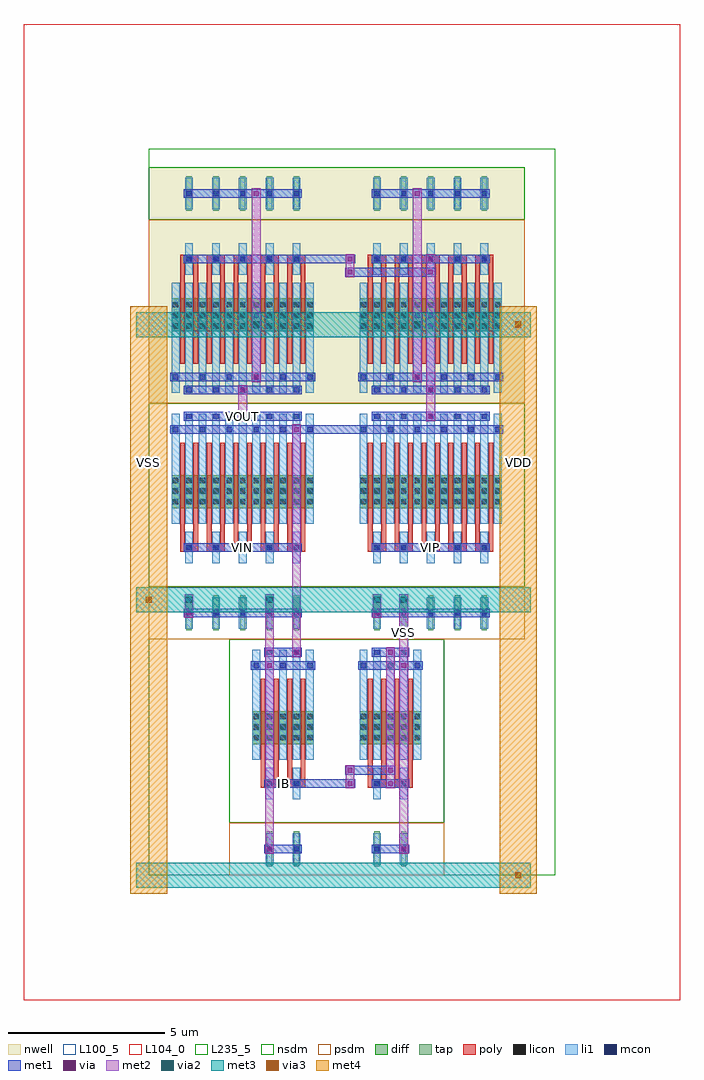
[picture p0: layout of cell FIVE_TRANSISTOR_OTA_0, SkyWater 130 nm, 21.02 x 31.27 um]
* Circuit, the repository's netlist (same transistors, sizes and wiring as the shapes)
* NGSPICE file created from FIVE_TRANSISTOR_OTA_0.ext - technology: sky130A

.subckt NMOS_4T_70086367_X5_Y1_1772456397 a_230_462# a_200_252# a_147_462# a_241_1232#
X0 a_230_462# a_200_252# a_147_462# a_241_1232# sky130_fd_pr__nfet_01v8 ad=0.147 pd=1.33 as=0.147 ps=1.33 w=1.05 l=0.15 M=10
.ends

.subckt NMOS_S_12526843_X2_Y1_1772456398 a_230_462# a_200_252# a_147_462#
X0 a_230_462# a_200_252# a_147_462# a_147_462# sky130_fd_pr__nfet_01v8 ad=0.147 pd=1.33 as=0.147 ps=1.33 w=1.05 l=0.15 M=4
.ends

.subckt DCL_NMOS_S_92974257_X2_Y1_1772456395 a_200_252# a_147_462#
X0 a_200_252# a_200_252# a_147_462# a_147_462# sky130_fd_pr__nfet_01v8 ad=0.147 pd=1.33 as=0.147 ps=1.33 w=1.05 l=0.15 M=4
.ends

.subckt PMOS_S_72546662_X5_Y1_1772456399 a_230_462# a_200_252# w_0_0#
X0 a_230_462# a_200_252# w_0_0# w_0_0# sky130_fd_pr__pfet_01v8 ad=0.147 pd=1.33 as=0.147 ps=1.33 w=1.05 l=0.15 M=10
.ends

.subckt DCL_PMOS_S_56423641_X5_Y1_1772456396 a_200_252# w_0_0#
X0 a_200_252# a_200_252# w_0_0# w_0_0# sky130_fd_pr__pfet_01v8 ad=0.147 pd=1.33 as=0.147 ps=1.33 w=1.05 l=0.15 M=10
.ends

.subckt FIVE_TRANSISTOR_OTA_0 IB VOUT VIP VIN VSS VDD
XNMOS_4T_70086367_X5_Y1_1772456397_0 VOUT VIN m1_914_1400# VSS NMOS_4T_70086367_X5_Y1_1772456397
XNMOS_4T_70086367_X5_Y1_1772456397_1 m1_946_3920# VIP m1_914_1400# VSS NMOS_4T_70086367_X5_Y1_1772456397
XNMOS_S_12526843_X2_Y1_1772456398_0 m1_914_1400# IB VSS NMOS_S_12526843_X2_Y1_1772456398
XDCL_NMOS_S_92974257_X2_Y1_1772456395_0 IB VSS DCL_NMOS_S_92974257_X2_Y1_1772456395
XPMOS_S_72546662_X5_Y1_1772456399_0 VOUT m1_946_3920# VDD PMOS_S_72546662_X5_Y1_1772456399
XDCL_PMOS_S_56423641_X5_Y1_1772456396_0 m1_946_3920# VDD DCL_PMOS_S_56423641_X5_Y1_1772456396
.ends

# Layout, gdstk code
from math import pi, radians
import gdstk
lib = gdstk.Library(unit=1e-6, precision=1e-09)
def R(c, l, rs):  # rectangles x0, y0, x1, y1
    for r in rs: c.add(gdstk.rectangle(r[:2], r[2:], *l))
def A(c, l, x, y, w, h, nx, ny, dx, dy):  # array of equal rectangles
    R(c, l, [(x+i*dx, y+j*dy, x+i*dx+w, y+j*dy+h) for i in range(nx) for j in range(ny)])
def P(c, l, *ps):  # polygons
    for p in ps: c.add(gdstk.Polygon(p, *l))
nwell = (64, 20)
diff = (65, 20)
tap = (65, 44)
poly = (66, 20)
licon = (66, 44)
li1 = (67, 20)
mcon = (67, 44)
met1 = (68, 20)
via = (68, 44)
met2 = (69, 20)
via2 = (69, 44)
met3 = (70, 20)
via3 = (70, 44)
met4 = (71, 20)
nsdm = (93, 44)
psdm = (94, 20)
L100_5 = (100, 5)
L104_0 = (104, 0)
L235_5 = (235, 5)

dcl_nmos_s_92974257_x2_y = lib.new_cell('DCL_NMOS_S_92974257_X2_Y1_1772456395')
R(dcl_nmos_s_92974257_x2_y, diff, [(0.735,2.31,2.705,3.36)])
R(dcl_nmos_s_92974257_x2_y, tap, [(1.205,6.16,1.375,7.28), (2.065,6.16,2.235,7.28)])
A(dcl_nmos_s_92974257_x2_y, poly, 1, 1.26, 0.15, 3.36, 4, 1, 0.43, 0)
R(dcl_nmos_s_92974257_x2_y, poly, [(1,4.485,1.58,4.755), (1.86,4.485,2.44,4.755)])
A(dcl_nmos_s_92974257_x2_y, licon, 0.775, 2.39, 0.17, 0.17, 3, 3, 0.43, 0.34)
A(dcl_nmos_s_92974257_x2_y, licon, 1.635, 2.39, 0.17, 0.17, 3, 3, 0.43, 0.34)
R(dcl_nmos_s_92974257_x2_y, licon, [(1.205,4.535,1.375,4.705), (2.065,4.535,2.235,4.705), (1.205,6.635,1.375,6.805), (2.065,6.635,2.235,6.805)])
A(dcl_nmos_s_92974257_x2_y, li1, 0.735, 0.335, 0.25, 3.53, 5, 1, 0.43, 0)
R(dcl_nmos_s_92974257_x2_y, li1, [(1.165,4.115,1.415,5.125), (2.025,4.115,2.275,5.125), (1.165,6.215,1.415,7.225), (2.025,6.215,2.275,7.225)])
A(dcl_nmos_s_92974257_x2_y, mcon, 0.775, 0.755, 0.17, 0.17, 3, 1, 0.86, 0)
R(dcl_nmos_s_92974257_x2_y, mcon, [(1.205,0.335,1.375,0.505), (2.065,0.335,2.235,0.505), (1.205,4.535,1.375,4.705), (2.065,4.535,2.235,4.705), (1.205,6.635,1.375,6.805), (2.065,6.635,2.235,6.805)])
R(dcl_nmos_s_92974257_x2_y, met1, [(1.12,0.28,2.32,0.56), (0.69,0.7,2.75,0.98), (1.12,4.48,2.32,4.76), (1.12,6.58,2.32,6.86)])
R(dcl_nmos_s_92974257_x2_y, via, [(1.645,0.345,1.795,0.495), (2.075,0.765,2.225,0.915), (1.645,4.545,1.795,4.695), (2.075,6.645,2.225,6.795)])
R(dcl_nmos_s_92974257_x2_y, met2, [(1.58,0.26,1.86,4.78), (2.01,0.68,2.29,6.88)])
R(dcl_nmos_s_92974257_x2_y, nsdm, [(0,0,3.44,5.88)])
R(dcl_nmos_s_92974257_x2_y, psdm, [(0,5.88,3.44,7.56)])
R(dcl_nmos_s_92974257_x2_y, L100_5, [(0,0,3.44,7.56)])

dcl_pmos_s_56423641_x5_y = lib.new_cell('DCL_PMOS_S_56423641_X5_Y1_1772456396')
R(dcl_pmos_s_56423641_x5_y, nwell, [(0,0,6.02,7.56)])
R(dcl_pmos_s_56423641_x5_y, diff, [(0.735,2.31,5.285,3.36)])
A(dcl_pmos_s_56423641_x5_y, tap, 1.205, 6.16, 0.17, 1.12, 5, 1, 0.86, 0)
A(dcl_pmos_s_56423641_x5_y, poly, 1, 1.26, 0.15, 3.36, 10, 1, 0.43, 0)
A(dcl_pmos_s_56423641_x5_y, poly, 1, 4.485, 0.58, 0.27, 5, 1, 0.86, 0)
A(dcl_pmos_s_56423641_x5_y, licon, 0.775, 2.39, 0.17, 0.17, 3, 3, 0.43, 0.34)
A(dcl_pmos_s_56423641_x5_y, licon, 1.635, 2.39, 0.17, 0.17, 3, 3, 0.43, 0.34)
A(dcl_pmos_s_56423641_x5_y, licon, 2.495, 2.39, 0.17, 0.17, 3, 3, 0.43, 0.34)
A(dcl_pmos_s_56423641_x5_y, licon, 3.355, 2.39, 0.17, 0.17, 3, 3, 0.43, 0.34)
A(dcl_pmos_s_56423641_x5_y, licon, 4.215, 2.39, 0.17, 0.17, 3, 3, 0.43, 0.34)
A(dcl_pmos_s_56423641_x5_y, licon, 1.205, 4.535, 0.17, 0.17, 5, 2, 0.86, 2.1)
A(dcl_pmos_s_56423641_x5_y, li1, 0.735, 0.335, 0.25, 3.53, 11, 1, 0.43, 0)
A(dcl_pmos_s_56423641_x5_y, li1, 1.165, 4.115, 0.25, 1.01, 5, 2, 0.86, 2.1)
A(dcl_pmos_s_56423641_x5_y, mcon, 1.205, 0.335, 0.17, 0.17, 5, 2, 0.86, 4.2)
A(dcl_pmos_s_56423641_x5_y, mcon, 0.775, 0.755, 0.17, 0.17, 6, 1, 0.86, 0)
A(dcl_pmos_s_56423641_x5_y, mcon, 1.205, 6.635, 0.17, 0.17, 5, 1, 0.86, 0)
R(dcl_pmos_s_56423641_x5_y, met1, [(1.12,0.28,4.9,0.56), (0.69,0.7,5.33,0.98), (1.12,4.48,4.9,4.76), (1.12,6.58,4.9,6.86)])
R(dcl_pmos_s_56423641_x5_y, via, [(2.935,0.345,3.085,0.495), (3.365,0.765,3.515,0.915), (2.935,4.545,3.085,4.695), (3.365,6.645,3.515,6.795)])
R(dcl_pmos_s_56423641_x5_y, met2, [(2.87,0.26,3.15,4.78), (3.3,0.68,3.58,6.88)])
R(dcl_pmos_s_56423641_x5_y, nsdm, [(0,5.88,6.02,7.56)])
R(dcl_pmos_s_56423641_x5_y, psdm, [(0,0,6.02,5.88)])
R(dcl_pmos_s_56423641_x5_y, L100_5, [(0,0,6.02,7.56)])

nmos_s_12526843_x2_y1_17 = lib.new_cell('NMOS_S_12526843_X2_Y1_1772456398')
R(nmos_s_12526843_x2_y1_17, diff, [(0.735,2.31,2.705,3.36)])
R(nmos_s_12526843_x2_y1_17, tap, [(1.205,6.16,1.375,7.28), (2.065,6.16,2.235,7.28)])
A(nmos_s_12526843_x2_y1_17, poly, 1, 1.26, 0.15, 3.36, 4, 1, 0.43, 0)
R(nmos_s_12526843_x2_y1_17, poly, [(1,4.485,1.58,4.755), (1.86,4.485,2.44,4.755)])
A(nmos_s_12526843_x2_y1_17, licon, 0.775, 2.39, 0.17, 0.17, 3, 3, 0.43, 0.34)
A(nmos_s_12526843_x2_y1_17, licon, 1.635, 2.39, 0.17, 0.17, 3, 3, 0.43, 0.34)
R(nmos_s_12526843_x2_y1_17, licon, [(1.205,4.535,1.375,4.705), (2.065,4.535,2.235,4.705), (1.205,6.635,1.375,6.805), (2.065,6.635,2.235,6.805)])
A(nmos_s_12526843_x2_y1_17, li1, 0.735, 0.335, 0.25, 3.53, 5, 1, 0.43, 0)
R(nmos_s_12526843_x2_y1_17, li1, [(1.165,4.115,1.415,5.125), (2.025,4.115,2.275,5.125), (1.165,6.215,1.415,7.225), (2.025,6.215,2.275,7.225)])
A(nmos_s_12526843_x2_y1_17, mcon, 0.775, 0.755, 0.17, 0.17, 3, 1, 0.86, 0)
R(nmos_s_12526843_x2_y1_17, mcon, [(1.205,0.335,1.375,0.505), (2.065,0.335,2.235,0.505), (1.205,4.535,1.375,4.705), (2.065,4.535,2.235,4.705), (1.205,6.635,1.375,6.805), (2.065,6.635,2.235,6.805)])
R(nmos_s_12526843_x2_y1_17, met1, [(1.12,0.28,2.32,0.56), (0.69,0.7,2.75,0.98), (1.12,4.48,2.32,4.76), (1.12,6.58,2.32,6.86)])
R(nmos_s_12526843_x2_y1_17, via, [(2.075,0.765,2.225,0.915), (2.075,6.645,2.225,6.795)])
R(nmos_s_12526843_x2_y1_17, met2, [(2.01,0.68,2.29,6.88)])
R(nmos_s_12526843_x2_y1_17, nsdm, [(0,0,3.44,5.88)])
R(nmos_s_12526843_x2_y1_17, psdm, [(0,5.88,3.44,7.56)])
R(nmos_s_12526843_x2_y1_17, L100_5, [(0,0,3.44,7.56)])

pmos_s_72546662_x5_y1_17 = lib.new_cell('PMOS_S_72546662_X5_Y1_1772456399')
R(pmos_s_72546662_x5_y1_17, nwell, [(0,0,6.02,7.56)])
R(pmos_s_72546662_x5_y1_17, diff, [(0.735,2.31,5.285,3.36)])
A(pmos_s_72546662_x5_y1_17, tap, 1.205, 6.16, 0.17, 1.12, 5, 1, 0.86, 0)
A(pmos_s_72546662_x5_y1_17, poly, 1, 1.26, 0.15, 3.36, 10, 1, 0.43, 0)
A(pmos_s_72546662_x5_y1_17, poly, 1, 4.485, 0.58, 0.27, 5, 1, 0.86, 0)
A(pmos_s_72546662_x5_y1_17, licon, 0.775, 2.39, 0.17, 0.17, 3, 3, 0.43, 0.34)
A(pmos_s_72546662_x5_y1_17, licon, 1.635, 2.39, 0.17, 0.17, 3, 3, 0.43, 0.34)
A(pmos_s_72546662_x5_y1_17, licon, 2.495, 2.39, 0.17, 0.17, 3, 3, 0.43, 0.34)
A(pmos_s_72546662_x5_y1_17, licon, 3.355, 2.39, 0.17, 0.17, 3, 3, 0.43, 0.34)
A(pmos_s_72546662_x5_y1_17, licon, 4.215, 2.39, 0.17, 0.17, 3, 3, 0.43, 0.34)
A(pmos_s_72546662_x5_y1_17, licon, 1.205, 4.535, 0.17, 0.17, 5, 2, 0.86, 2.1)
A(pmos_s_72546662_x5_y1_17, li1, 0.735, 0.335, 0.25, 3.53, 11, 1, 0.43, 0)
A(pmos_s_72546662_x5_y1_17, li1, 1.165, 4.115, 0.25, 1.01, 5, 2, 0.86, 2.1)
A(pmos_s_72546662_x5_y1_17, mcon, 1.205, 0.335, 0.17, 0.17, 5, 2, 0.86, 4.2)
A(pmos_s_72546662_x5_y1_17, mcon, 0.775, 0.755, 0.17, 0.17, 6, 1, 0.86, 0)
A(pmos_s_72546662_x5_y1_17, mcon, 1.205, 6.635, 0.17, 0.17, 5, 1, 0.86, 0)
R(pmos_s_72546662_x5_y1_17, met1, [(1.12,0.28,4.9,0.56), (0.69,0.7,5.33,0.98), (1.12,4.48,4.9,4.76), (1.12,6.58,4.9,6.86)])
R(pmos_s_72546662_x5_y1_17, via, [(3.365,0.765,3.515,0.915), (3.365,6.645,3.515,6.795)])
R(pmos_s_72546662_x5_y1_17, met2, [(3.3,0.68,3.58,6.88)])
R(pmos_s_72546662_x5_y1_17, nsdm, [(0,5.88,6.02,7.56)])
R(pmos_s_72546662_x5_y1_17, psdm, [(0,0,6.02,5.88)])
R(pmos_s_72546662_x5_y1_17, L100_5, [(0,0,6.02,7.56)])

nmos_4t_70086367_x5_y1_1 = lib.new_cell('NMOS_4T_70086367_X5_Y1_1772456397')
R(nmos_4t_70086367_x5_y1_1, diff, [(0.735,2.31,5.285,3.36)])
A(nmos_4t_70086367_x5_y1_1, tap, 1.205, 6.16, 0.17, 1.12, 5, 1, 0.86, 0)
A(nmos_4t_70086367_x5_y1_1, poly, 1, 1.26, 0.15, 3.36, 10, 1, 0.43, 0)
A(nmos_4t_70086367_x5_y1_1, poly, 1, 4.485, 0.58, 0.27, 5, 1, 0.86, 0)
A(nmos_4t_70086367_x5_y1_1, licon, 0.775, 2.39, 0.17, 0.17, 3, 3, 0.43, 0.34)
A(nmos_4t_70086367_x5_y1_1, licon, 1.635, 2.39, 0.17, 0.17, 3, 3, 0.43, 0.34)
A(nmos_4t_70086367_x5_y1_1, licon, 2.495, 2.39, 0.17, 0.17, 3, 3, 0.43, 0.34)
A(nmos_4t_70086367_x5_y1_1, licon, 3.355, 2.39, 0.17, 0.17, 3, 3, 0.43, 0.34)
A(nmos_4t_70086367_x5_y1_1, licon, 4.215, 2.39, 0.17, 0.17, 3, 3, 0.43, 0.34)
A(nmos_4t_70086367_x5_y1_1, licon, 1.205, 4.535, 0.17, 0.17, 5, 2, 0.86, 2.1)
A(nmos_4t_70086367_x5_y1_1, li1, 0.735, 0.335, 0.25, 3.53, 11, 1, 0.43, 0)
A(nmos_4t_70086367_x5_y1_1, li1, 1.165, 4.115, 0.25, 1.01, 5, 2, 0.86, 2.1)
A(nmos_4t_70086367_x5_y1_1, mcon, 1.205, 0.335, 0.17, 0.17, 5, 2, 0.86, 4.2)
A(nmos_4t_70086367_x5_y1_1, mcon, 0.775, 0.755, 0.17, 0.17, 6, 1, 0.86, 0)
A(nmos_4t_70086367_x5_y1_1, mcon, 1.205, 6.635, 0.17, 0.17, 5, 1, 0.86, 0)
R(nmos_4t_70086367_x5_y1_1, met1, [(1.12,0.28,4.9,0.56), (0.69,0.7,5.33,0.98), (1.12,4.48,4.9,4.76), (1.12,6.58,4.9,6.86)])
R(nmos_4t_70086367_x5_y1_1, nsdm, [(0,0,6.02,5.88)])
R(nmos_4t_70086367_x5_y1_1, psdm, [(0,5.88,6.02,7.56)])
R(nmos_4t_70086367_x5_y1_1, L100_5, [(0,0,6.02,7.56)])

five_transistor_ota_0 = lib.new_cell('FIVE_TRANSISTOR_OTA_0')
R(five_transistor_ota_0, met1, [(4.73,2.8,6.45,3.08), (6.29,2.8,6.61,3.08), (6.29,2.8,6.61,3.08), (6.29,3.22,6.61,3.5), (6.29,3.22,6.61,3.5), (6.45,3.22,7.74,3.5), (7.58,3.22,7.9,3.5), (7.58,3.22,7.9,3.5), (4.57,7,4.89,7.28), (4.57,7,4.89,7.28), (4.57,7,4.89,7.28), (4.57,7,4.89,7.28), (1.13,8.26,1.45,8.54), (1.13,8.26,1.45,8.54), (7.15,8.26,7.47,8.54), (7.15,8.26,7.47,8.54), (7.15,8.26,7.47,8.54), (4.57,14.14,4.89,14.42), (4.57,14.14,4.89,14.42), (4.57,14.14,4.89,14.42), (4.57,14.14,4.89,14.42), (5.16,14.14,6.88,14.42), (2.85,14.56,3.17,14.84), (2.85,14.56,3.17,14.84), (8.87,14.56,9.19,14.84), (8.87,14.56,9.19,14.84), (2.85,15.4,3.17,15.68), (2.85,15.4,3.17,15.68), (6.29,19.18,6.61,19.46), (6.29,19.18,6.61,19.46), (6.29,19.18,6.61,19.46), (6.29,19.18,6.61,19.46), (6.45,19.18,9.03,19.46), (8.87,19.18,9.19,19.46), (8.87,19.18,9.19,19.46), (8.87,19.18,9.19,19.46), (8.87,19.18,9.19,19.46), (4.73,19.6,6.45,19.88), (6.29,19.6,6.61,19.88), (6.29,19.6,6.61,19.88), (6.29,19.6,6.61,19.88), (6.29,19.6,6.61,19.88)])
P(five_transistor_ota_0, met1, [(0,0),(0,0),(0,0),(0,0)],
  [(0,0),(0,0),(0,0),(0,0)],
  [(0,0),(0,0),(0,0),(0,0)],
  [(0,0),(0,0),(0,0),(0,0)],
  [(0,0),(0,0),(0,0),(0,0)],
  [(0,0),(0,0),(0,0),(0,0)],
  [(0,0),(0,0),(0,0),(0,0)],
  [(0,0),(0,0),(0,0),(0,0)],
  [(0,0),(0,0),(0,0),(0,0)],
  [(0,0),(0,0),(0,0),(0,0)],
  [(0,0),(0,0),(0,0),(0,0)],
  [(0,0),(0,0),(0,0),(0,0)],
  [(0,0),(0,0),(0,0),(0,0)],
  [(0,0),(0,0),(0,0),(0,0)],
  [(0,0),(0,0),(0,0),(0,0)],
  [(0,0),(0,0),(0,0),(0,0)])
R(five_transistor_ota_0, via, [(6.375,2.865,6.525,3.015), (6.375,2.865,6.525,3.015), (6.375,3.285,6.525,3.435), (6.375,3.285,6.525,3.435), (7.665,3.285,7.815,3.435), (7.665,3.285,7.815,3.435), (4.655,7.065,4.805,7.215), (4.655,7.065,4.805,7.215), (4.655,7.065,4.805,7.215), (4.655,7.065,4.805,7.215), (1.215,8.325,1.365,8.475), (1.215,8.325,1.365,8.475), (7.235,8.325,7.385,8.475), (7.235,8.325,7.385,8.475), (7.235,8.325,7.385,8.475), (4.655,14.205,4.805,14.355), (4.655,14.205,4.805,14.355), (4.655,14.205,4.805,14.355), (4.655,14.205,4.805,14.355), (2.935,14.625,3.085,14.775), (2.935,14.625,3.085,14.775), (8.955,14.625,9.105,14.775), (8.955,14.625,9.105,14.775), (2.935,15.465,3.085,15.615), (2.935,15.465,3.085,15.615), (6.375,19.245,6.525,19.395), (6.375,19.245,6.525,19.395), (6.375,19.245,6.525,19.395), (6.375,19.245,6.525,19.395), (8.955,19.245,9.105,19.395), (8.955,19.245,9.105,19.395), (8.955,19.245,9.105,19.395), (8.955,19.245,9.105,19.395), (6.375,19.665,6.525,19.815), (6.375,19.665,6.525,19.815), (6.375,19.665,6.525,19.815), (6.375,19.665,6.525,19.815)])
R(five_transistor_ota_0, met2, [(6.31,2.78,6.59,3.1), (6.31,2.78,6.59,3.1), (6.31,2.94,6.59,3.36), (6.31,3.2,6.59,3.52), (6.31,3.2,6.59,3.52), (7.6,3.2,7.88,3.52), (7.6,3.2,7.88,3.52), (3.73,6.72,4.01,8.82), (8.03,6.72,8.31,8.82), (4.59,6.98,4.87,7.3), (4.59,6.98,4.87,7.3), (4.59,6.98,4.87,7.3), (4.59,6.98,4.87,7.3), (4.59,7.14,4.87,14.28), (1.15,8.24,1.43,8.56), (1.15,8.24,1.43,8.56), (7.17,8.24,7.45,8.56), (7.17,8.24,7.45,8.56), (7.17,8.24,7.45,8.56), (1.15,8.4,1.43,8.82), (7.17,8.4,7.45,8.82), (1.15,8.635,1.43,9.005), (1.15,8.635,1.43,9.005), (3.73,8.635,4.01,9.005), (3.73,8.635,4.01,9.005), (3.73,8.635,4.01,9.005), (3.73,8.635,4.01,9.005), (7.17,8.635,7.45,9.005), (7.17,8.635,7.45,9.005), (7.17,8.635,7.45,9.005), (8.03,8.635,8.31,9.005), (8.03,8.635,8.31,9.005), (8.03,8.635,8.31,9.005), (8.03,8.635,8.31,9.005), (8.03,8.635,8.31,9.005), (4.59,14.12,4.87,14.44), (4.59,14.12,4.87,14.44), (4.59,14.12,4.87,14.44), (4.59,14.12,4.87,14.44), (2.87,14.54,3.15,14.86), (2.87,14.54,3.15,14.86), (8.89,14.54,9.17,14.86), (8.89,14.54,9.17,14.86), (2.87,14.7,3.15,15.54), (8.89,14.7,9.17,15.54), (2.87,15.38,3.15,15.7), (2.87,15.38,3.15,15.7), (3.3,17.455,3.58,17.825), (3.3,17.455,3.58,17.825), (8.46,17.455,8.74,17.825), (8.46,17.455,8.74,17.825), (8.46,17.455,8.74,17.825), (6.31,19.16,6.59,19.48), (6.31,19.16,6.59,19.48), (6.31,19.16,6.59,19.48), (6.31,19.16,6.59,19.48), (8.89,19.16,9.17,19.48), (8.89,19.16,9.17,19.48), (8.89,19.16,9.17,19.48), (8.89,19.16,9.17,19.48), (6.31,19.32,6.59,19.74), (6.31,19.58,6.59,19.9), (6.31,19.58,6.59,19.9), (6.31,19.58,6.59,19.9), (6.31,19.58,6.59,19.9)])
P(five_transistor_ota_0, met2, [(0,0),(0,0),(0,0),(0,0)],
  [(0,0),(0,0),(0,0),(0,0)],
  [(0,0),(0,0),(0,0),(0,0)],
  [(0,0),(0,0),(0,0),(0,0)],
  [(0,0),(0,0),(0,0),(0,0)],
  [(0,0),(0,0),(0,0),(0,0)])
R(five_transistor_ota_0, via2, [(1.19,8.72,1.39,8.92), (1.19,8.72,1.39,8.92), (3.77,8.72,3.97,8.92), (3.77,8.72,3.97,8.92), (3.77,8.72,3.97,8.92), (3.77,8.72,3.97,8.92), (7.21,8.72,7.41,8.92), (7.21,8.72,7.41,8.92), (7.21,8.72,7.41,8.92), (8.07,8.72,8.27,8.92), (8.07,8.72,8.27,8.92), (8.07,8.72,8.27,8.92), (8.07,8.72,8.27,8.92), (8.07,8.72,8.27,8.92), (3.34,17.54,3.54,17.74), (3.34,17.54,3.54,17.74), (8.5,17.54,8.7,17.74), (8.5,17.54,8.7,17.74), (8.5,17.54,8.7,17.74)])
A(five_transistor_ota_0, met3, -0.4, -0.4, 4.24, 0.8, 3, 3, 3.44, 8.82)
A(five_transistor_ota_0, met3, 9.92, -0.4, 2.32, 0.8, 1, 3, 0, 8.82)
R(five_transistor_ota_0, met3, [(11.675,-0.4,12.005,0.4), (-0.165,8.42,0.165,9.22), (1.125,8.42,1.455,9.22), (1.125,8.42,1.455,9.22), (3.705,8.42,4.035,9.22), (3.705,8.42,4.035,9.22), (3.705,8.42,4.035,9.22), (3.705,8.42,4.035,9.22), (7.145,8.42,7.475,9.22), (7.145,8.42,7.475,9.22), (7.145,8.42,7.475,9.22), (8.005,8.42,8.335,9.22), (8.005,8.42,8.335,9.22), (8.005,8.42,8.335,9.22), (8.005,8.42,8.335,9.22), (8.005,8.42,8.335,9.22), (3.275,17.24,3.605,18.04), (3.275,17.24,3.605,18.04), (8.435,17.24,8.765,18.04), (8.435,17.24,8.765,18.04), (8.435,17.24,8.765,18.04), (11.675,17.24,12.005,18.04)])
R(five_transistor_ota_0, via3, [(11.74,-0.1,11.94,0.1), (-0.1,8.72,0.1,8.92), (11.74,17.54,11.94,17.74)])
R(five_transistor_ota_0, met4, [(-0.59,-0.59,0.59,9.41), (11.25,-0.59,12.43,9.41), (11.25,-0.165,12.43,0.165), (-0.59,8.23,0.59,18.23), (11.25,8.23,12.43,18.23), (-0.59,8.655,0.59,8.985), (11.25,17.475,12.43,17.805)])
R(five_transistor_ota_0, L104_0, [(-4,-4,17.02,27.27)])
R(five_transistor_ota_0, L235_5, [(0,0,13.02,23.27)])
five_transistor_ota_0.add(gdstk.Reference(dcl_nmos_s_92974257_x2_y, (6.02,7.56), x_reflection=True))
five_transistor_ota_0.add(gdstk.Reference(dcl_pmos_s_56423641_x5_y, (12.04,15.12), rotation=pi, x_reflection=True))
five_transistor_ota_0.add(gdstk.Reference(nmos_s_12526843_x2_y1_17, (6.02,7.56), rotation=pi))
five_transistor_ota_0.add(gdstk.Reference(pmos_s_72546662_x5_y1_17, (0,15.12)))
five_transistor_ota_0.add(gdstk.Reference(nmos_4t_70086367_x5_y1_1, (12.04,15.12), rotation=pi))
five_transistor_ota_0.add(gdstk.Reference(nmos_4t_70086367_x5_y1_1, (0,15.12), x_reflection=True))
five_transistor_ota_0.add(gdstk.Label('IB', (4.3,2.94), layer=68, texttype=5))
five_transistor_ota_0.add(gdstk.Label('VOUT', (3.01,14.7), layer=68, texttype=5))
five_transistor_ota_0.add(gdstk.Label('VIP', (9.03,10.5), layer=68, texttype=5))
five_transistor_ota_0.add(gdstk.Label('VIN', (3.01,10.5), layer=68, texttype=5))
five_transistor_ota_0.add(gdstk.Label('VSS', (8.17,7.77), layer=69, texttype=5))
five_transistor_ota_0.add(gdstk.Label('VSS', (0,13.23), layer=71, texttype=5))
five_transistor_ota_0.add(gdstk.Label('VSS', (0,13.23), layer=71, texttype=5))
five_transistor_ota_0.add(gdstk.Label('VSS', (0,13.23), layer=71, texttype=5))
five_transistor_ota_0.add(gdstk.Label('VSS', (0,13.23), layer=71, texttype=5))
five_transistor_ota_0.add(gdstk.Label('VSS', (0,13.23), layer=71, texttype=5))
five_transistor_ota_0.add(gdstk.Label('VSS', (0,13.23), layer=71, texttype=5))
five_transistor_ota_0.add(gdstk.Label('VSS', (0,13.23), layer=71, texttype=5))
five_transistor_ota_0.add(gdstk.Label('VSS', (0,13.23), layer=71, texttype=5))
five_transistor_ota_0.add(gdstk.Label('VSS', (0,13.23), layer=71, texttype=5))
five_transistor_ota_0.add(gdstk.Label('VSS', (0,13.23), layer=71, texttype=5))
five_transistor_ota_0.add(gdstk.Label('VDD', (11.84,13.23), layer=71, texttype=5))
five_transistor_ota_0.add(gdstk.Label('VDD', (11.84,13.23), layer=71, texttype=5))
five_transistor_ota_0.add(gdstk.Label('VDD', (11.84,13.23), layer=71, texttype=5))
five_transistor_ota_0.add(gdstk.Label('VDD', (11.84,13.23), layer=71, texttype=5))

lib.write_gds('FIVE_TRANSISTOR_OTA_0.gds')
